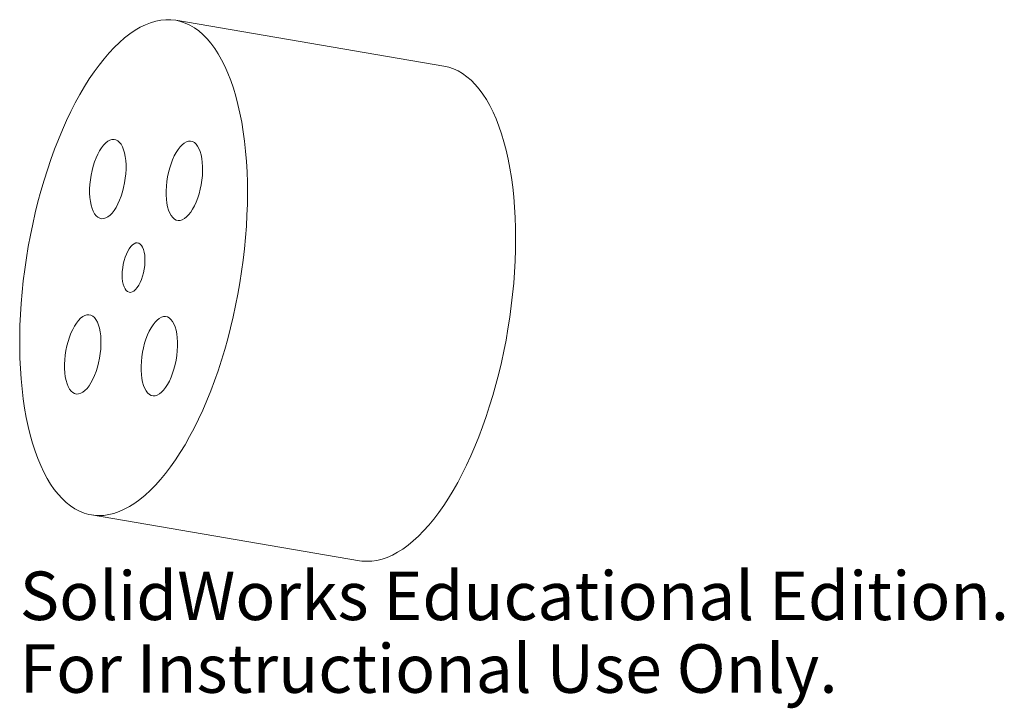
# Model space of a CAD drawing. Units: millimetres. Extents: x -38.1 to 60.1, y -39.4 to 29.3.
import ezdxf

# ---------------------------------------------------------------- set-up
doc = ezdxf.new("R2010")
doc.units = ezdxf.units.MM
doc.styles.add('SLDTEXTSTYLE0', font='TXT', dxfattribs={"width": 0.7})

msp = doc.modelspace()

# ---------------------------------------------------------------- linework, layer by layer
at = {"color": 7, "linetype": 'Continuous', "lineweight": 15}
for p, q in [((4.204, 24.644), (-22.524, 29.204)), ((-30.933, -20.084), (-4.204, -24.644))]:
    msp.add_line(p, q, dxfattribs=at)
at = {"color": 7, "linetype": 'Continuous', "lineweight": 15, "flags": 128}
for points in [[(-21.6, -13.09), (-21.141, -12.278), (-20.694, -11.431), (-20.259, -10.551), (-19.839, -9.639), (-19.432, -8.697), (-19.041, -7.727), (-18.666, -6.731), (-18.308, -5.711), (-17.968, -4.67), (-17.646, -3.61), (-17.343, -2.532), (-17.06, -1.439), (-16.798, -0.334), (-16.556, 0.782), (-16.336, 1.905), (-16.137, 3.034), (-15.961, 4.166), (-15.807, 5.3), (-15.677, 6.431), (-15.569, 7.559), (-15.485, 8.68), (-15.425, 9.793), (-15.388, 10.894), (-15.376, 11.983), (-15.387, 13.055), (-15.422, 14.11), (-15.481, 15.145), (-15.563, 16.158), (-15.669, 17.146), (-15.799, 18.107), (-15.951, 19.04), (-16.126, 19.943), (-16.323, 20.814), (-16.542, 21.65), (-16.782, 22.45), (-17.044, 23.213), (-17.326, 23.936), (-17.627, 24.619), (-17.948, 25.259), (-18.287, 25.856), (-18.644, 26.408), (-19.018, 26.914), (-19.408, 27.373), (-19.813, 27.785), (-20.234, 28.147), (-20.667, 28.46), (-21.114, 28.722), (-21.572, 28.934), (-22.041, 29.094), (-22.52, 29.203), (-23.008, 29.26), (-23.504, 29.265), (-24.006, 29.218), (-24.514, 29.12), (-25.027, 28.969), (-25.543, 28.767), (-26.062, 28.515), (-26.583, 28.212), (-27.103, 27.859), (-27.623, 27.457), (-28.141, 27.007), (-28.656, 26.51), (-29.167, 25.967), (-29.672, 25.379), (-30.172, 24.747), (-30.664, 24.072), (-31.148, 23.356), (-31.623, 22.601), (-32.088, 21.808), (-32.541, 20.979), (-32.982, 20.115), (-33.41, 19.219), (-33.823, 18.291), (-34.222, 17.335), (-34.605, 16.352), (-34.972, 15.344), (-35.321, 14.313), (-35.652, 13.262), (-35.965, 12.193), (-36.258, 11.107), (-36.53, 10.008), (-36.783, 8.897), (-37.014, 7.777), (-37.223, 6.651), (-37.411, 5.52), (-37.576, 4.387), (-37.718, 3.254), (-37.837, 2.124), (-37.933, 1), (-38.005, -0.118), (-38.053, -1.225), (-38.078, -2.32), (-38.078, -3.401), (-38.055, -4.465), (-38.008, -5.51), (-37.938, -6.534), (-37.843, -7.535), (-37.726, -8.51), (-37.585, -9.458), (-37.421, -10.376), (-37.235, -11.263), (-37.027, -12.116), (-36.797, -12.935), (-36.546, -13.716), (-36.275, -14.459), (-35.983, -15.163), (-35.672, -15.824), (-35.342, -16.443), (-34.994, -17.018), (-34.628, -17.547), (-34.246, -18.03), (-33.848, -18.465), (-33.435, -18.852), (-33.008, -19.19), (-32.568, -19.477), (-32.115, -19.715), (-31.652, -19.901), (-31.177, -20.035), (-30.694, -20.118), (-30.202, -20.149), (-29.703, -20.128), (-29.197, -20.056), (-28.687, -19.931), (-28.172, -19.755), (-27.654, -19.528), (-27.135, -19.25), (-26.614, -18.922), (-26.094, -18.544), (-25.575, -18.118), (-25.058, -17.645), (-24.545, -17.124), (-24.037, -16.558), (-23.534, -15.948), (-23.038, -15.295), (-22.549, -14.599), (-22.07, -13.864), (-21.6, -13.09)], [(5.128, -17.649), (5.587, -16.838), (6.034, -15.991), (6.469, -15.111), (6.89, -14.199), (7.296, -13.257), (7.687, -12.287), (8.062, -11.291), (8.42, -10.271), (8.761, -9.23), (9.082, -8.17), (9.385, -7.092), (9.668, -5.999), (9.931, -4.894), (10.172, -3.778), (10.393, -2.655), (10.591, -1.526), (10.768, -0.394), (10.921, 0.74), (11.052, 1.871), (11.159, 2.999), (11.243, 4.12), (11.303, 5.233), (11.34, 6.334), (11.353, 7.423), (11.341, 8.495), (11.306, 9.55), (11.247, 10.585), (11.165, 11.598), (11.059, 12.586), (10.93, 13.547), (10.778, 14.481), (10.603, 15.383), (10.406, 16.254), (10.186, 17.09), (9.946, 17.89), (9.685, 18.653), (9.403, 19.376), (9.101, 20.059), (8.781, 20.699), (8.441, 21.296), (8.084, 21.848), (7.711, 22.354), (7.32, 22.814), (6.915, 23.225), (6.495, 23.587), (6.061, 23.9), (5.615, 24.162), (5.156, 24.374), (4.687, 24.534), (4.208, 24.643), (4.204, 24.644)], [(-28.472, 10.561), (-28.666, 10.259), (-28.868, 9.999), (-29.076, 9.785), (-29.287, 9.619), (-29.498, 9.505), (-29.706, 9.443), (-29.908, 9.434), (-30.102, 9.479), (-30.286, 9.577), (-30.456, 9.726), (-30.61, 9.924), (-30.746, 10.169), (-30.863, 10.458), (-30.958, 10.787), (-31.031, 11.15), (-31.08, 11.544), (-31.106, 11.963), (-31.106, 12.4), (-31.082, 12.852), (-31.034, 13.31), (-30.963, 13.769), (-30.869, 14.224), (-30.753, 14.666), (-30.618, 15.092), (-30.465, 15.494), (-30.296, 15.868), (-30.113, 16.209), (-29.919, 16.511), (-29.717, 16.771), (-29.509, 16.985), (-29.299, 17.15), (-29.088, 17.264), (-28.88, 17.326), (-28.677, 17.335), (-28.483, 17.29), (-28.299, 17.193), (-28.13, 17.044), (-27.975, 16.845), (-27.839, 16.6), (-27.723, 16.311), (-27.627, 15.983), (-27.554, 15.619), (-27.505, 15.225), (-27.48, 14.807), (-27.479, 14.369), (-27.503, 13.918), (-27.551, 13.459), (-27.622, 13), (-27.717, 12.546), (-27.832, 12.103), (-27.967, 11.677), (-28.12, 11.275), (-28.289, 10.901), (-28.472, 10.561)], [(-20.844, 10.383), (-21.037, 10.081), (-21.24, 9.821), (-21.447, 9.607), (-21.658, 9.441), (-21.869, 9.327), (-22.077, 9.265), (-22.28, 9.256), (-22.474, 9.301), (-22.657, 9.398), (-22.827, 9.547), (-22.981, 9.746), (-23.118, 9.991), (-23.234, 10.28), (-23.33, 10.609), (-23.403, 10.972), (-23.452, 11.366), (-23.477, 11.784), (-23.478, 12.222), (-23.454, 12.673), (-23.406, 13.132), (-23.335, 13.591), (-23.24, 14.045), (-23.125, 14.488), (-22.99, 14.914), (-22.836, 15.316), (-22.667, 15.69), (-22.485, 16.03), (-22.291, 16.333), (-22.089, 16.592), (-21.881, 16.807), (-21.67, 16.972), (-21.459, 17.086), (-21.251, 17.148), (-21.049, 17.157), (-20.854, 17.112), (-20.671, 17.015), (-20.501, 16.866), (-20.347, 16.667), (-20.211, 16.422), (-20.094, 16.133), (-19.999, 15.805), (-19.926, 15.441), (-19.877, 15.047), (-19.851, 14.629), (-19.851, 14.191), (-19.874, 13.74), (-19.922, 13.281), (-19.994, 12.822), (-20.088, 12.368), (-20.204, 11.925), (-20.339, 11.499), (-20.492, 11.097), (-20.661, 10.723), (-20.844, 10.383)], [(-26.216, 2.795), (-26.074, 3.066), (-25.946, 3.368), (-25.834, 3.696), (-25.742, 4.042), (-25.671, 4.399), (-25.622, 4.76), (-25.597, 5.117), (-25.596, 5.461), (-25.619, 5.787), (-25.666, 6.086), (-25.735, 6.353), (-25.826, 6.581), (-25.935, 6.767), (-26.062, 6.905), (-26.203, 6.993), (-26.355, 7.03), (-26.515, 7.014), (-26.68, 6.945), (-26.846, 6.826), (-27.009, 6.659), (-27.166, 6.446), (-27.314, 6.194), (-27.449, 5.907), (-27.569, 5.591), (-27.671, 5.253), (-27.753, 4.9), (-27.814, 4.54), (-27.851, 4.18), (-27.864, 3.829), (-27.853, 3.493), (-27.818, 3.18), (-27.759, 2.896), (-27.679, 2.648), (-27.579, 2.44), (-27.46, 2.278), (-27.326, 2.164), (-27.179, 2.102), (-27.022, 2.091), (-26.86, 2.134), (-26.694, 2.228), (-26.529, 2.372), (-26.369, 2.562), (-26.216, 2.795)], [(-30.972, -6.911), (-31.166, -7.213), (-31.368, -7.473), (-31.576, -7.687), (-31.787, -7.852), (-31.998, -7.966), (-32.206, -8.028), (-32.408, -8.037), (-32.602, -7.992), (-32.786, -7.895), (-32.956, -7.746), (-33.11, -7.547), (-33.246, -7.302), (-33.363, -7.013), (-33.458, -6.685), (-33.531, -6.321), (-33.58, -5.927), (-33.606, -5.509), (-33.606, -5.071), (-33.582, -4.62), (-33.534, -4.161), (-33.463, -3.702), (-33.369, -3.248), (-33.253, -2.805), (-33.118, -2.379), (-32.965, -1.977), (-32.796, -1.603), (-32.613, -1.263), (-32.419, -0.961), (-32.217, -0.701), (-32.009, -0.487), (-31.799, -0.321), (-31.588, -0.207), (-31.38, -0.145), (-31.177, -0.136), (-30.983, -0.181), (-30.799, -0.278), (-30.63, -0.428), (-30.475, -0.626), (-30.339, -0.871), (-30.223, -1.16), (-30.127, -1.489), (-30.054, -1.852), (-30.005, -2.246), (-29.98, -2.665), (-29.979, -3.102), (-30.003, -3.554), (-30.051, -4.012), (-30.122, -4.471), (-30.217, -4.926), (-30.332, -5.368), (-30.467, -5.794), (-30.62, -6.196), (-30.789, -6.57), (-30.972, -6.911)], [(-23.344, -7.089), (-23.537, -7.391), (-23.74, -7.651), (-23.947, -7.865), (-24.158, -8.03), (-24.369, -8.145), (-24.577, -8.207), (-24.78, -8.215), (-24.974, -8.171), (-25.157, -8.073), (-25.327, -7.924), (-25.481, -7.725), (-25.618, -7.48), (-25.734, -7.191), (-25.83, -6.863), (-25.903, -6.499), (-25.952, -6.106), (-25.977, -5.687), (-25.978, -5.249), (-25.954, -4.798), (-25.906, -4.339), (-25.835, -3.88), (-25.74, -3.426), (-25.625, -2.983), (-25.49, -2.558), (-25.336, -2.155), (-25.167, -1.781), (-24.985, -1.441), (-24.791, -1.139), (-24.589, -0.879), (-24.381, -0.665), (-24.17, -0.499), (-23.959, -0.385), (-23.751, -0.323), (-23.549, -0.314), (-23.354, -0.359), (-23.171, -0.457), (-23.001, -0.606), (-22.847, -0.804), (-22.711, -1.05), (-22.594, -1.338), (-22.499, -1.667), (-22.426, -2.03), (-22.377, -2.424), (-22.351, -2.843), (-22.351, -3.281), (-22.374, -3.732), (-22.422, -4.19), (-22.494, -4.649), (-22.588, -5.104), (-22.704, -5.547), (-22.839, -5.972), (-22.992, -6.374), (-23.161, -6.748), (-23.344, -7.089)], [(-4.204, -24.644), (-3.965, -24.678), (-3.474, -24.709), (-2.974, -24.688), (-2.469, -24.615), (-1.958, -24.491), (-1.444, -24.315), (-0.926, -24.088), (-0.406, -23.81), (0.114, -23.482), (0.635, -23.104), (1.154, -22.678), (1.67, -22.205), (2.183, -21.684), (2.692, -21.118), (3.195, -20.508), (3.691, -19.855), (4.179, -19.159), (4.659, -18.424), (5.128, -17.649)]]:
    msp.add_lwpolyline(points, dxfattribs=at)

# ---------------------------------------------------------------- texts
at = {"color": 7, "linetype": 'Continuous', "char_height": 4.83362, "attachment_point": 1, "style": 'SLDTEXTSTYLE0'}
for s, insert in [('SolidWorks Educational Edition.', (-38.078, -25.729)), ('For Instructional Use Only.', (-38.078, -32.979))]:
    msp.add_mtext(s, dxfattribs=dict(at, insert=insert))

doc.saveas('drawing.dxf')
